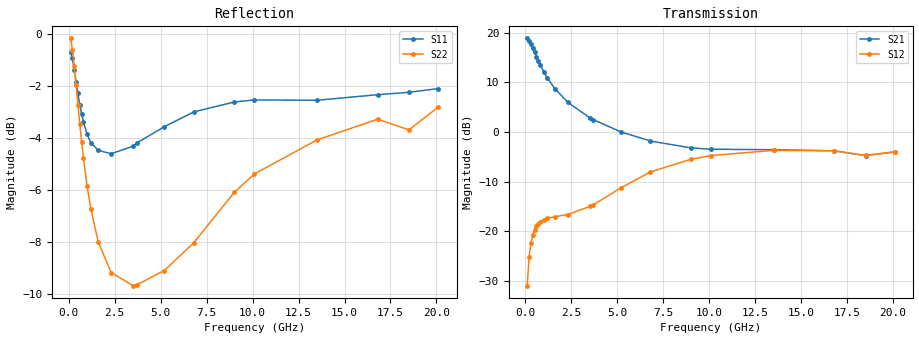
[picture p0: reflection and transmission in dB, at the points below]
!  Infineon Technologies AG
! BFR380L3 , PF131585-7, No.6, Th 09.10.01, soldered on pcb-board, measured with PP GSG850
!  Vce=3.5 V,  Ic=2.5 mA
! Common Emitter S-Parameters:  15. November 2001
#  GHz  S  MA  R  50
! f  S11  S21  S12  S22
! GHz  Mag  Ang  Mag  Ang  Mag  Ang  Mag  Ang
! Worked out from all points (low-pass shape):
!   201 points, 100 MHz to 20.1 GHz, reference 50 ohm
!   highest |S21| = 18.83 dB at 100 MHz (marker M1); lowest = -4.8 dB at 18.5 GHz (marker M2)
!   |S21| within 3 dB of the highest: start of sweep to 519.3 MHz
!   lowest |S11| = -4.6 dB at 2.3 GHz (marker M3), VSWR 3.85, Z = 13 - j0.272 ohm
!   |S11| at or under -10 dB: nowhere
!   |S22| runs from -9.7 to -0.2 dB; largest |S21 - S12| = 8.7
!   S11 on the Smith chart (normalised r, x): 100 MHz: 1.41, -5.61; 500 MHz: 0.30, -1.12; 1.2 GHz: 0.27, -0.36; 3.7 GHz: 0.25, +0.25; 9 GHz: 0.32, +1.04; 20.1 GHz: 1.00, +2.53
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0.1  0.9213 -19.1  8.737 167.0  0.02831 78.1  0.9801 -10.2
0.2  0.8967 -36.7  8.196 155.0  0.05448 69.4  0.9328 -19.6
0.3  0.8531 -53.7  7.599 144.1  0.0759 61.1  0.8664 -27.6
0.4  0.8087 -68.3  6.941 134.7  0.09163 54.1  0.7967 -34.2
0.5  0.768 -81.3  6.304 126.6  0.1038 48.6  0.7307 -39.5
0.6  0.7302 -92.4  5.711 119.7  0.1128 44.2  0.6711 -43.7
0.7  0.7006 -102.5  5.206 113.7  0.1193 40.8  0.6204 -47.1
0.8  0.6768 -111.3  4.752 108.4  0.1242 38.1  0.5764 -49.9
1  0.6405 -125.9  4.027 99.7  0.1308 34.3  0.5089 -54.2
1.2  0.6175 -137.9  3.477 92.4  0.1349 32.3  0.4604 -57.4
1.6  0.5968 -156.6  2.729 80.6  0.14 31.1  0.3981 -62.8
2.3  0.5877 -179.3  1.989 64.7  0.1473 34.1  0.3471 -72.1
3.5  0.6075 153.8  1.386 44.0  0.1778 44.5  0.3274 -91.7
3.7  0.6163 150.7  1.325 41.4  0.1847 45.7  0.3286 -96.0
5.2  0.6625 126.6  0.9997 23.1  0.2737 49.0  0.3502 -126.1
6.8  0.7073 105.7  0.8093 10.4  0.3947 42.1  0.3961 -160.7
8.999999  0.7392 84.8  0.6904 0.4  0.5302 25.5  0.495 160.5
10.1  0.746 76.3  0.6691 -3.5  0.5783 16.6  0.5373 143.6
13.5  0.7449 58.5  0.6616 -17.1  0.6514 -7.8  0.6247 105.2
16.8  0.7635 46.8  0.6438 -29.7  0.646 -25.0  0.6849 80.1
18.5  0.7716 45.4  0.5779 -37.6  0.5788 -33.7  0.6533 73.7
20.1  0.7846 38.3  0.6277 -42.1  0.6316 -38.9  0.7225 62.4
